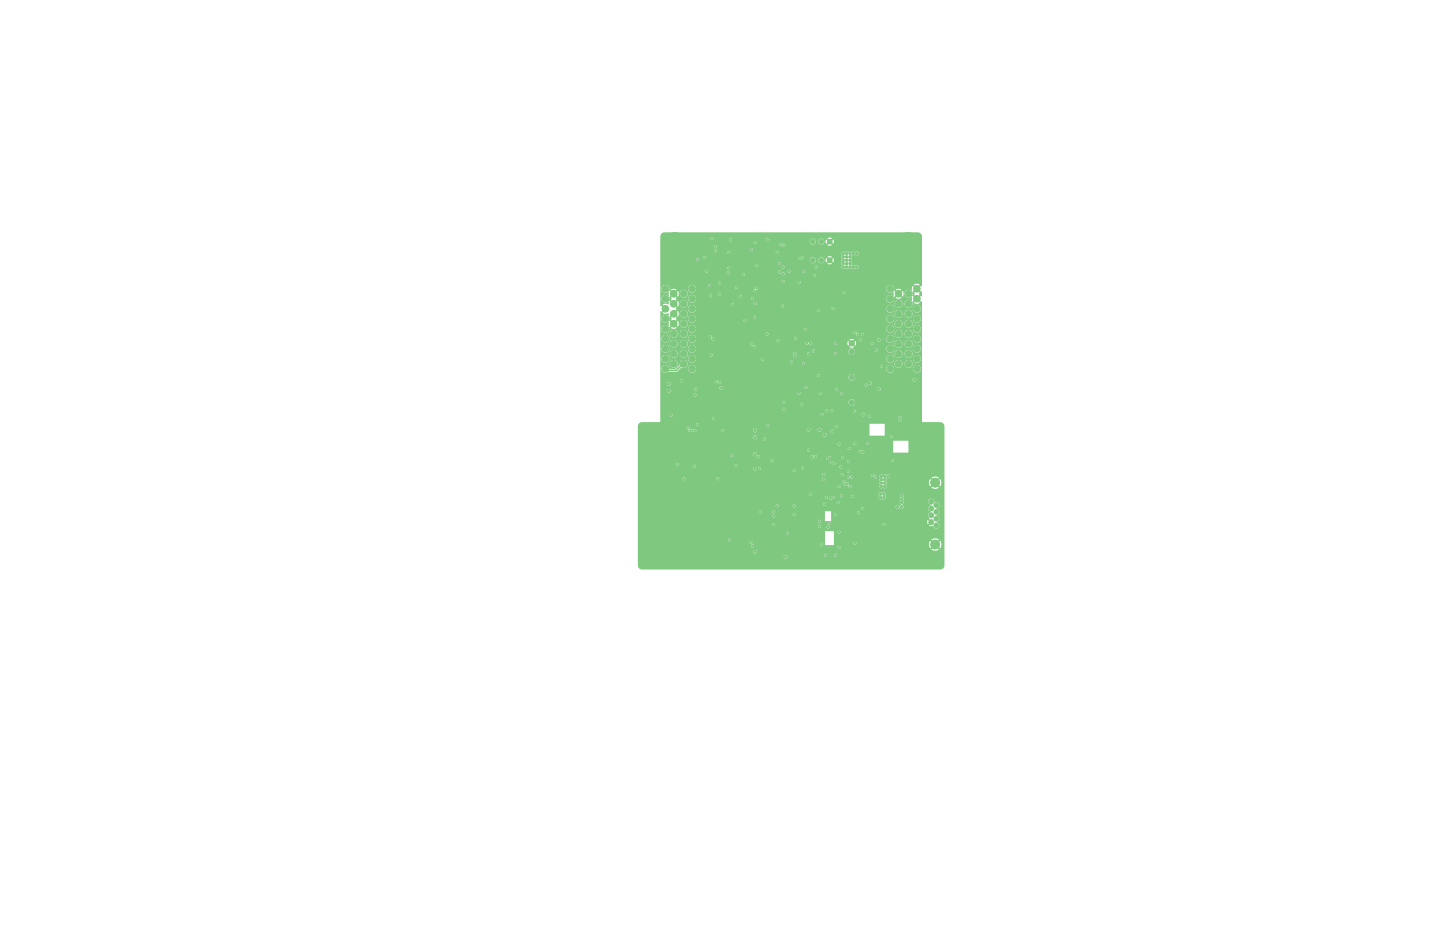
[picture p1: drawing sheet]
<svg xmlns="http://www.w3.org/2000/svg" width="432mm" height="279mm" viewBox="0 0 432 279" stroke-linecap="round" stroke-linejoin="round" font-family="sans-serif">
<g fill="#7fc87f" stroke="#7fc87f" stroke-width=".3">
<circle cx="255.4" cy="102.9" r=".8"/>
<circle cx="255.4" cy="105.5" r=".8"/>
<circle cx="255.4" cy="113.1" r=".8"/>
<circle cx="255.4" cy="120.7" r=".8"/>
<circle cx="202.3" cy="72.9" r="3.2"/>
<circle cx="278.5" cy="130.1" r="3.2"/>
<circle cx="196" cy="165.7" r="3.2"/>
<circle cx="207.5" cy="86.6" r="1"/>
<circle cx="207.5" cy="89.6" r="1"/>
<circle cx="207.5" cy="92.6" r="1"/>
<circle cx="207.5" cy="95.6" r="1"/>
<circle cx="207.5" cy="98.6" r="1"/>
<circle cx="207.5" cy="101.6" r="1"/>
<circle cx="207.5" cy="104.6" r="1"/>
<circle cx="207.5" cy="107.6" r="1"/>
<circle cx="207.5" cy="110.6" r="1"/>
<circle cx="205" cy="88.1" r="1"/>
<circle cx="205" cy="91.1" r="1"/>
<circle cx="205" cy="94.1" r="1"/>
<circle cx="205" cy="97.1" r="1"/>
<circle cx="205" cy="100.1" r="1"/>
<circle cx="205" cy="103.1" r="1"/>
<circle cx="205" cy="106.1" r="1"/>
<circle cx="205" cy="109.1" r="1"/>
<circle cx="202" cy="88.1" r="1"/>
<circle cx="202" cy="91.1" r="1"/>
<circle cx="202" cy="94.1" r="1"/>
<circle cx="202" cy="97.1" r="1"/>
<circle cx="202" cy="100.1" r="1"/>
<circle cx="202" cy="103.1" r="1"/>
<circle cx="202" cy="106.1" r="1"/>
<circle cx="202" cy="109.1" r="1"/>
<circle cx="199.5" cy="86.6" r="1"/>
<circle cx="199.5" cy="89.6" r="1"/>
<circle cx="199.5" cy="92.6" r="1"/>
<circle cx="199.5" cy="95.6" r="1"/>
<circle cx="199.5" cy="98.6" r="1"/>
<circle cx="199.5" cy="101.6" r="1"/>
<circle cx="199.5" cy="104.6" r="1"/>
<circle cx="199.5" cy="107.6" r="1"/>
<circle cx="199.5" cy="110.6" r="1"/>
<circle cx="243.7" cy="78" r=".72"/>
<circle cx="246.3" cy="78" r=".72"/>
<circle cx="248.8" cy="78" r=".72"/>
<circle cx="266.9" cy="110.6" r="1"/>
<circle cx="266.9" cy="107.6" r="1"/>
<circle cx="266.9" cy="104.6" r="1"/>
<circle cx="266.9" cy="101.6" r="1"/>
<circle cx="266.9" cy="98.6" r="1"/>
<circle cx="266.9" cy="95.6" r="1"/>
<circle cx="266.9" cy="92.6" r="1"/>
<circle cx="266.9" cy="89.6" r="1"/>
<circle cx="266.9" cy="86.6" r="1"/>
<circle cx="269.4" cy="109.1" r="1"/>
<circle cx="269.4" cy="106.1" r="1"/>
<circle cx="269.4" cy="103.1" r="1"/>
<circle cx="269.4" cy="100.1" r="1"/>
<circle cx="269.4" cy="97.1" r="1"/>
<circle cx="269.4" cy="94.1" r="1"/>
<circle cx="269.4" cy="91.1" r="1"/>
<circle cx="269.4" cy="88.1" r="1"/>
<circle cx="272.4" cy="109.1" r="1"/>
<circle cx="272.4" cy="106.1" r="1"/>
<circle cx="272.4" cy="103.1" r="1"/>
<circle cx="272.4" cy="100.1" r="1"/>
<circle cx="272.4" cy="97.1" r="1"/>
<circle cx="272.4" cy="94.1" r="1"/>
<circle cx="272.4" cy="91.1" r="1"/>
<circle cx="272.4" cy="88.1" r="1"/>
<circle cx="274.9" cy="110.6" r="1"/>
<circle cx="274.9" cy="107.6" r="1"/>
<circle cx="274.9" cy="104.6" r="1"/>
<circle cx="274.9" cy="101.6" r="1"/>
<circle cx="274.9" cy="98.6" r="1"/>
<circle cx="274.9" cy="95.6" r="1"/>
<circle cx="274.9" cy="92.6" r="1"/>
<circle cx="274.9" cy="89.6" r="1"/>
<circle cx="274.9" cy="86.6" r="1"/>
<circle cx="272.2" cy="72.9" r="3.2"/>
<circle cx="243.7" cy="72.4" r=".72"/>
<circle cx="246.3" cy="72.4" r=".72"/>
<circle cx="248.8" cy="72.4" r=".72"/>
<circle cx="280.8" cy="151.4" r=".72"/>
<circle cx="279.2" cy="150.4" r=".72"/>
<circle cx="279.2" cy="152.4" r=".72"/>
<circle cx="279.2" cy="154.5" r=".72"/>
<circle cx="280.8" cy="153.5" r=".72"/>
<circle cx="280.8" cy="155.5" r=".72"/>
<circle cx="280.8" cy="157.5" r=".72"/>
<circle cx="279.2" cy="156.5" r=".72"/>
<circle cx="280.4" cy="163.2" r="1.35"/>
<circle cx="280.4" cy="144.7" r="1.35"/>
<circle cx="232" cy="158.5" r=".25"/>
<circle cx="264.8" cy="135.4" r=".25"/>
<circle cx="229.2" cy="135.4" r=".25"/>
<circle cx="219.1" cy="134.2" r=".25"/>
<circle cx="257.9" cy="88.9" r=".25"/>
<circle cx="218.6" cy="73.3" r=".25"/>
<circle cx="233.8" cy="88.9" r=".25"/>
<circle cx="220.1" cy="78.3" r=".25"/>
<circle cx="263" cy="74.5" r=".38"/>
<circle cx="214.2" cy="141.5" r=".25"/>
<circle cx="253.6" cy="161.6" r=".25"/>
<circle cx="251.6" cy="100.6" r=".25"/>
<circle cx="214.5" cy="77.8" r=".25"/>
<circle cx="264" cy="72.4" r=".38"/>
<circle cx="263" cy="71.4" r=".38"/>
<circle cx="217.8" cy="129.1" r=".25"/>
<circle cx="243.2" cy="98.9" r=".25"/>
<circle cx="263" cy="73.5" r=".38"/>
<circle cx="261" cy="84.1" r=".25"/>
<circle cx="207.4" cy="140.3" r=".25"/>
<circle cx="240.7" cy="145.6" r=".25"/>
<circle cx="217.8" cy="125.5" r=".25"/>
<circle cx="251.6" cy="128.3" r=".25"/>
<circle cx="229.2" cy="94.8" r=".25"/>
<circle cx="264.8" cy="151.9" r=".38"/>
<circle cx="264" cy="71.4" r=".38"/>
<circle cx="224.4" cy="125.5" r=".25"/>
<circle cx="252.3" cy="97.8" r=".25"/>
<circle cx="270.6" cy="81.6" r=".38"/>
<circle cx="271.4" cy="79.8" r=".38"/>
<circle cx="224.4" cy="120.4" r=".25"/>
<circle cx="265" cy="71.4" r=".38"/>
<circle cx="269.4" cy="128.1" r=".25"/>
<circle cx="265.8" cy="151.9" r=".38"/>
<circle cx="247" cy="144.6" r=".25"/>
<circle cx="254.1" cy="133.7" r=".25"/>
<circle cx="245.7" cy="152.2" r=".25"/>
<circle cx="269.9" cy="156.3" r=".25"/>
<circle cx="269.6" cy="81.6" r=".38"/>
<circle cx="265" cy="72.4" r=".38"/>
<circle cx="259.1" cy="119.4" r=".3"/>
<circle cx="242.9" cy="87.7" r=".3"/>
<circle cx="265" cy="133.1" r=".25"/>
<circle cx="257.9" cy="113.3" r=".25"/>
<circle cx="208.2" cy="133.1" r=".25"/>
<circle cx="214" cy="91.5" r=".25"/>
<circle cx="231" cy="83.6" r=".25"/>
<circle cx="227.5" cy="146.1" r=".25"/>
<circle cx="270.9" cy="144.6" r=".38"/>
<circle cx="213" cy="111.8" r=".25"/>
<circle cx="246" cy="109" r=".25"/>
<circle cx="219.1" cy="137.7" r=".25"/>
<circle cx="271.4" cy="80.8" r=".38"/>
<circle cx="206.4" cy="143.6" r=".25"/>
<circle cx="216.8" cy="108.5" r=".25"/>
<circle cx="270.6" cy="78.5" r=".38"/>
<circle cx="235.1" cy="114.9" r=".25"/>
<circle cx="246.3" cy="161.3" r=".25"/>
<circle cx="273.2" cy="136.7" r=".25"/>
<circle cx="245.7" cy="120.7" r=".25"/>
<circle cx="207.1" cy="124.5" r=".25"/>
<circle cx="257.9" cy="96.1" r=".25"/>
<circle cx="260" cy="97.3" r=".25"/>
<circle cx="254.6" cy="165.4" r=".25"/>
<circle cx="247" cy="164.4" r=".25"/>
<circle cx="242.7" cy="166.4" r=".25"/>
<circle cx="231" cy="118.4" r=".25"/>
<circle cx="207.6" cy="161.6" r=".25"/>
<circle cx="249.3" cy="151.2" r=".25"/>
<circle cx="269.6" cy="78.5" r=".38"/>
<circle cx="206.1" cy="80.3" r=".25"/>
<circle cx="235.3" cy="96.8" r=".25"/>
<circle cx="236.1" cy="154.7" r=".25"/>
<circle cx="233" cy="124.8" r=".25"/>
<circle cx="250.1" cy="108.3" r=".25"/>
<circle cx="224.4" cy="123" r=".25"/>
<circle cx="253.1" cy="89.7" r=".25"/>
<circle cx="233" cy="104.2" r=".25"/>
<circle cx="210.2" cy="143.6" r=".25"/>
<circle cx="270.9" cy="143.3" r=".38"/>
<circle cx="267.3" cy="124.3" r=".25"/>
<circle cx="252.9" cy="165.4" r=".25"/>
<circle cx="221.1" cy="105.2" r=".25"/>
<circle cx="269.9" cy="144.6" r=".38"/>
<circle cx="233.3" cy="107.2" r=".25"/>
<circle cx="213" cy="116.9" r=".25"/>
<circle cx="269.9" cy="143.3" r=".38"/>
<circle cx="246.5" cy="115.4" r=".25"/>
<circle cx="254.9" cy="148.9" r=".25"/>
<circle cx="239.9" cy="123.2" r=".25"/>
<circle cx="219.8" cy="95.3" r=".25"/>
<circle cx="240.2" cy="131.4" r=".25"/>
<circle cx="211.5" cy="161.6" r=".25"/>
<circle cx="250.8" cy="113.6" r=".25"/>
<circle cx="250.1" cy="125.8" r=".25"/>
<circle cx="242.7" cy="127.8" r=".25"/>
<circle cx="265.8" cy="150.9" r=".38"/>
<circle cx="262.8" cy="158.3" r=".25"/>
<circle cx="246" cy="101.9" r=".25"/>
<circle cx="245.7" cy="133.1" r=".25"/>
<circle cx="217.8" cy="127.6" r=".25"/>
<circle cx="257.9" cy="104.9" r=".25"/>
<circle cx="203.1" cy="135.7" r=".25"/>
<circle cx="229" cy="107" r=".25"/>
<circle cx="220.9" cy="85.1" r=".25"/>
<circle cx="242.2" cy="96.3" r=".25"/>
<circle cx="230" cy="76.5" r=".25"/>
<circle cx="263" cy="72.4" r=".38"/>
<circle cx="269.9" cy="160.1" r=".25"/>
<circle cx="229.7" cy="124.8" r=".25"/>
<circle cx="208.2" cy="119.4" r=".25"/>
<circle cx="247" cy="138.2" r=".25"/>
<circle cx="266.8" cy="151.9" r=".38"/>
<circle cx="230.5" cy="86.4" r=".25"/>
<circle cx="248.1" cy="138.3" r=".25"/>
<circle cx="240.2" cy="75.2" r=".25"/>
<circle cx="248.5" cy="93.6" r=".25"/>
<circle cx="247.3" cy="122.5" r=".25"/>
<circle cx="264.8" cy="150.9" r=".38"/>
<circle cx="219.8" cy="98.3" r=".25"/>
<circle cx="212.7" cy="143.6" r=".25"/>
<circle cx="241.7" cy="157.5" r=".25"/>
<circle cx="262.3" cy="124.5" r=".25"/>
<circle cx="253.1" cy="128.3" r=".25"/>
<circle cx="268.9" cy="143.3" r=".38"/>
<circle cx="259" cy="128.8" r=".3"/>
<circle cx="264" cy="153.2" r=".25"/>
<circle cx="201.8" cy="142.3" r=".25"/>
<circle cx="259.5" cy="137.7" r=".25"/>
<circle cx="209.4" cy="140" r=".25"/>
<circle cx="235.8" cy="145.6" r=".25"/>
<circle cx="238.4" cy="127.3" r=".25"/>
<circle cx="258.2" cy="146.4" r=".25"/>
<circle cx="241.2" cy="165.1" r=".38"/>
<circle cx="217.8" cy="71.9" r=".25"/>
<circle cx="259" cy="133.9" r=".25"/>
<circle cx="256.3" cy="132.9" r=".25"/>
<circle cx="247.5" cy="166.4" r=".25"/>
<circle cx="257.9" cy="135.4" r=".25"/>
<circle cx="243.6" cy="137" r=".25"/>
<circle cx="265.3" cy="143.8" r=".38"/>
<circle cx="267.6" cy="138" r=".25"/>
<circle cx="242.9" cy="148.1" r=".25"/>
<circle cx="264.3" cy="144.8" r=".38"/>
<circle cx="260.2" cy="132.9" r=".25"/>
<circle cx="236.1" cy="159.8" r=".25"/>
<circle cx="265.3" cy="144.8" r=".38"/>
<circle cx="246.3" cy="163.1" r=".25"/>
<circle cx="255.6" cy="148.9" r=".25"/>
<circle cx="247.3" cy="151.2" r=".25"/>
<circle cx="264.3" cy="145.8" r=".38"/>
<circle cx="265.3" cy="142.8" r=".38"/>
<circle cx="250.6" cy="166.4" r=".25"/>
<circle cx="264.3" cy="142.8" r=".38"/>
<circle cx="205.1" cy="143.6" r=".25"/>
<circle cx="245.7" cy="156.3" r=".25"/>
<circle cx="266.3" cy="142.8" r=".38"/>
<circle cx="264.3" cy="143.8" r=".38"/>
<circle cx="265.3" cy="145.8" r=".38"/>
<circle cx="253.9" cy="79" r=".38"/>
<circle cx="252.9" cy="78" r=".38"/>
<circle cx="208.2" cy="139.7" r=".25"/>
<circle cx="267.3" cy="130.9" r=".25"/>
<circle cx="229.2" cy="131.6" r=".25"/>
<circle cx="218.6" cy="75.7" r=".25"/>
<circle cx="252.9" cy="79" r=".38"/>
<circle cx="252.9" cy="77" r=".38"/>
<circle cx="270.4" cy="151.9" r=".38"/>
<circle cx="226.2" cy="87.2" r=".25"/>
<circle cx="256.9" cy="76" r=".38"/>
<circle cx="241.4" cy="98.9" r=".25"/>
<circle cx="253.9" cy="80.1" r=".38"/>
<circle cx="253.1" cy="87.7" r=".25"/>
<circle cx="230.2" cy="127.6" r=".25"/>
<circle cx="264" cy="148.1" r=".38"/>
<circle cx="265" cy="148.1" r=".38"/>
<circle cx="253.9" cy="77" r=".38"/>
<circle cx="253.9" cy="78" r=".38"/>
<circle cx="253.9" cy="76" r=".38"/>
<circle cx="239.9" cy="77.5" r=".25"/>
<circle cx="226.2" cy="95" r=".25"/>
<circle cx="208.4" cy="118.4" r=".25"/>
<circle cx="252.9" cy="76" r=".38"/>
<circle cx="255.9" cy="76" r=".38"/>
<circle cx="255.9" cy="80.1" r=".38"/>
<circle cx="265" cy="149.1" r=".38"/>
<circle cx="256.9" cy="80.1" r=".38"/>
<circle cx="213.5" cy="71.4" r=".25"/>
<circle cx="269.1" cy="151.9" r=".38"/>
<circle cx="264" cy="149.1" r=".38"/>
<circle cx="254.9" cy="79" r=".38"/>
<circle cx="270.4" cy="150.7" r=".38"/>
<circle cx="208.7" cy="116.6" r=".25"/>
<circle cx="254.9" cy="80.1" r=".38"/>
<circle cx="222.1" cy="88.9" r=".25"/>
<circle cx="254.9" cy="76" r=".38"/>
<circle cx="270.4" cy="148.6" r=".38"/>
<circle cx="254.9" cy="78" r=".38"/>
<circle cx="257.9" cy="101.9" r=".25"/>
<circle cx="270.4" cy="149.7" r=".38"/>
<circle cx="252.9" cy="80.1" r=".38"/>
<circle cx="260.8" cy="124.8" r=".25"/>
<circle cx="215.3" cy="143.6" r=".25"/>
<circle cx="239.6" cy="84.6" r=".25"/>
<circle cx="218.3" cy="81.8" r=".25"/>
<circle cx="254.9" cy="77" r=".38"/>
<circle cx="219.7" cy="91.3" r=".25"/>
<circle cx="234.6" cy="91.7" r=".25"/>
<circle cx="226.4" cy="140.5" r=".38"/>
<circle cx="226.4" cy="129.1" r=".38"/>
<circle cx="216.3" cy="116.4" r=".38"/>
<circle cx="226.4" cy="131.1" r=".38"/>
<circle cx="274.2" cy="113.8" r=".38"/>
<circle cx="226.4" cy="136.2" r=".38"/>
<circle cx="226.4" cy="165.4" r=".38"/>
<circle cx="215.8" cy="114.6" r=".25"/>
<circle cx="254.6" cy="134.4" r=".25"/>
<circle cx="206.9" cy="129.1" r=".25"/>
<circle cx="208.4" cy="129.1" r=".25"/>
<circle cx="207.6" cy="129.1" r=".25"/>
<circle cx="201.3" cy="124.5" r=".25"/>
<circle cx="239.6" cy="117.9" r=".25"/>
<circle cx="251.6" cy="133.1" r=".25"/>
<circle cx="246.5" cy="124.3" r=".25"/>
<circle cx="263.5" cy="101.9" r=".3"/>
<circle cx="258.7" cy="135.4" r=".3"/>
<circle cx="240.6" cy="140.3" r=".25"/>
<circle cx="256.2" cy="123.2" r=".25"/>
<circle cx="264.3" cy="109.8" r=".25"/>
<circle cx="261.5" cy="102.9" r=".25"/>
<circle cx="265" cy="157.3" r=".25"/>
<circle cx="254.1" cy="145.1" r=".25"/>
<circle cx="250.6" cy="106" r=".25"/>
<circle cx="250.6" cy="102.9" r=".25"/>
<circle cx="245.9" cy="117.9" r=".25"/>
<circle cx="223.4" cy="96.1" r=".25"/>
<circle cx="218.6" cy="80.3" r=".25"/>
<circle cx="226.2" cy="103.9" r=".25"/>
<circle cx="242.5" cy="106" r=".25"/>
<circle cx="238.4" cy="106" r=".25"/>
<circle cx="250.8" cy="127.8" r=".25"/>
<circle cx="250.8" cy="116.6" r=".25"/>
<circle cx="238.1" cy="141" r=".25"/>
<circle cx="252.1" cy="140" r=".25"/>
<circle cx="233" cy="151.6" r=".25"/>
<circle cx="232" cy="154.7" r=".25"/>
<circle cx="249.6" cy="129.3" r=".38"/>
<circle cx="242.4" cy="128.8" r=".38"/>
<circle cx="247.3" cy="130.4" r=".38"/>
<circle cx="245.7" cy="128.8" r=".38"/>
<circle cx="259" cy="124.3" r=".38"/>
<circle cx="200.5" cy="117.1" r=".38"/>
<circle cx="252.3" cy="117.9" r=".25"/>
<circle cx="263.5" cy="116.6" r=".38"/>
<circle cx="249.5" cy="123.1" r=".25"/>
<circle cx="247.8" cy="123.2" r=".25"/>
<circle cx="204.3" cy="114.1" r=".3"/>
<circle cx="244.7" cy="80.1" r=".25"/>
<circle cx="234.1" cy="73.4" r=".25"/>
<circle cx="212.8" cy="85.6" r=".25"/>
<circle cx="212" cy="81.3" r=".25"/>
<circle cx="211.2" cy="77.3" r=".25"/>
<circle cx="213" cy="88.7" r=".25"/>
<circle cx="231.5" cy="138" r=".25"/>
<circle cx="242.5" cy="134.9" r=".25"/>
<circle cx="220.7" cy="139.6" r=".25"/>
<circle cx="250.1" cy="139" r=".25"/>
<circle cx="258.7" cy="100.3" r=".25"/>
<circle cx="240.7" cy="77.3" r=".25"/>
<circle cx="244.2" cy="82.6" r=".25"/>
<circle cx="249.8" cy="92.5" r=".25"/>
<circle cx="234.8" cy="80.1" r=".25"/>
<circle cx="233.8" cy="79" r=".25"/>
<circle cx="257.2" cy="100.3" r=".25"/>
<circle cx="236.6" cy="81.3" r=".25"/>
<circle cx="240.9" cy="81.3" r=".25"/>
<circle cx="245.5" cy="93" r=".25"/>
<circle cx="235.1" cy="73.5" r=".25"/>
<circle cx="220.9" cy="86.2" r=".25"/>
<circle cx="214.5" cy="75.2" r=".25"/>
<circle cx="225.7" cy="89.5" r=".25"/>
<circle cx="209.2" cy="77.8" r=".25"/>
<circle cx="226.4" cy="72.6" r=".25"/>
<circle cx="230" cy="71.9" r=".25"/>
<circle cx="219.1" cy="71.9" r=".25"/>
<circle cx="222.9" cy="82.3" r=".25"/>
<circle cx="214.5" cy="74" r=".25"/>
<circle cx="203.1" cy="139.2" r=".25"/>
<circle cx="249.4" cy="138.7" r=".25"/>
<circle cx="228.7" cy="107.7" r=".25"/>
<circle cx="225.4" cy="103.2" r=".25"/>
<circle cx="225.2" cy="162.6" r=".25"/>
<circle cx="218.8" cy="161.8" r=".25"/>
<circle cx="258.7" cy="152.4" r=".25"/>
<circle cx="225.7" cy="163.6" r=".25"/>
<circle cx="257.4" cy="153.7" r=".25"/>
<circle cx="232" cy="157.3" r=".25"/>
<circle cx="252.5" cy="142.3" r=".25"/>
<circle cx="247.8" cy="149.1" r=".25"/>
<circle cx="251.6" cy="159.6" r=".25"/>
<circle cx="254.4" cy="143" r=".25"/>
<circle cx="253.1" cy="144.3" r=".25"/>
<circle cx="244" cy="105.2" r=".25"/>
<circle cx="232" cy="153.5" r=".25"/>
<circle cx="228" cy="153.5" r=".25"/>
<circle cx="255.4" cy="143" r=".25"/>
<circle cx="253.4" cy="145.1" r=".25"/>
<circle cx="248.3" cy="158" r=".25"/>
<circle cx="245.7" cy="157.8" r=".25"/>
<circle cx="250.6" cy="154.3" r=".25"/>
<circle cx="248.8" cy="157" r=".25"/>
<circle cx="251.3" cy="150.7" r=".25"/>
<circle cx="249.8" cy="149.1" r=".25"/>
<circle cx="249.1" cy="149.4" r=".25"/>
<circle cx="254.4" cy="141.3" r=".25"/>
<circle cx="245.4" cy="112.6" r=".25"/>
<circle cx="238.6" cy="101.4" r=".25"/>
<circle cx="233.3" cy="102.2" r=".25"/>
<circle cx="241.9" cy="102.9" r=".25"/>
<circle cx="248.8" cy="137.2" r=".25"/>
<circle cx="259.7" cy="115.4" r=".25"/>
<circle cx="226.4" cy="91" r=".25"/>
<circle cx="234.8" cy="84.4" r=".25"/>
<circle cx="226.9" cy="86.4" r=".25"/>
<circle cx="226.9" cy="79.5" r=".25"/>
<circle cx="261" cy="114.9" r=".25"/>
<circle cx="248.1" cy="137.5" r=".25"/>
<circle cx="233.8" cy="81.5" r=".25"/>
<circle cx="233" cy="75.7" r=".25"/>
<circle cx="214.8" cy="114.3" r=".25"/>
<circle cx="216.8" cy="129.1" r=".25"/>
<circle cx="254.4" cy="138.3" r=".25"/>
<circle cx="227.7" cy="140.5" r=".25"/>
<circle cx="251.6" cy="164.1" r=".25"/>
<circle cx="256.4" cy="162.9" r=".25"/>
<circle cx="225.4" cy="74.7" r=".25"/>
<circle cx="234.8" cy="82.1" r=".25"/>
<circle cx="214" cy="125.5" r=".25"/>
<circle cx="209.2" cy="127.3" r=".25"/>
<circle cx="230" cy="100.1" r=".25"/>
<circle cx="256.4" cy="99.6" r=".25"/>
<circle cx="262.8" cy="104.9" r=".25"/>
<circle cx="240.3" cy="121.3" r=".25"/>
<circle cx="244.5" cy="136.9" r=".25"/>
<circle cx="235.1" cy="122.7" r=".25"/>
<circle cx="235.1" cy="120.7" r=".25"/>
<circle cx="261.7" cy="142.5" r=".25"/>
<circle cx="269.9" cy="125.3" r=".25"/>
<circle cx="262.5" cy="143" r=".25"/>
<circle cx="269.9" cy="126.1" r=".25"/>
<circle cx="240.9" cy="109" r=".25"/>
<circle cx="213" cy="100.9" r=".25"/>
<circle cx="213.2" cy="106.5" r=".25"/>
<circle cx="241.7" cy="116.1" r=".25"/>
<circle cx="242.9" cy="102.9" r=".25"/>
<circle cx="213.7" cy="101.6" r=".25"/>
<circle cx="215.8" cy="88.2" r=".25"/>
<circle cx="215.8" cy="84.8" r=".25"/>
<circle cx="238.1" cy="154.2" r=".25"/>
<circle cx="238.1" cy="151.7" r=".25"/>
<circle cx="200.5" cy="115.1" r=".38"/>
<circle cx="235.6" cy="166.9" r=".38"/>
<circle cx="227.5" cy="137" r=".25"/>
<circle cx="219.3" cy="136.4" r=".25"/>
<circle cx="206.3" cy="128.3" r=".25"/>
<circle cx="251.6" cy="145.8" r=".25"/>
<circle cx="252.3" cy="148.6" r=".25"/>
<circle cx="254.9" cy="145.8" r=".25"/>
<circle cx="247" cy="142.3" r=".25"/>
<circle cx="247" cy="143.8" r=".3"/>
<circle cx="252.6" cy="137.1" r=".25"/>
<circle cx="238.4" cy="106.7" r=".25"/>
<circle cx="237.4" cy="108.5" r=".25"/>
</g>
<path d="M204.8 109.1l-2 1.9h-2.8" fill="none" stroke="#7fc87f" stroke-width=".51"/>
<g fill="#7fc87f">
<path d="M198.4 70l.9-.4 76.1 .1 .8 .5 .3 .7v14.8h-.3l-.6 .6-.4-.4 .5-.6a1.5 1.5 0 0 0-1.6 0l.6 .6-.4 .4-.6-.6-.3 .8 .1 .9a1.25 1.25 0 0 0-1.9-.2 1.25 1.25 0 0 0 .1 1.9 1.25 1.25 0 0 0 1.8-.3l-.1 1.6a1.2 1.2 0 0 0-2 .1 1.2 1.2 0 0 0 1.1 1.8 1.2 1.2 0 0 0 1-1.8l.8-.6 .4 .3-.6 .6a1.49 1.49 0 0 0 1.7 0l-.6-.6 .4-.3 .6 .5h.3v35.9l.2 .2 5.4 .1 .7 .3 .4 .7v41.9a1.27 1.27 0 0 1-1.3 1.2h-89.8a1.27 1.27 0 0 1-.8-1.2v-2.5h43.7a.56 .56 0 0 0 .9 .4 .56 .56 0 0 0 0-.9 .56 .56 0 0 0-.9 .4l-43.7 .1v-.6h55.8l.4 .5 .4-.2 .1-.3h2.1a.44 .44 0 0 0 .6 .4 .44 .44 0 0 0 .2-.7 .44 .44 0 0 0-.7 .2l-2.2 .1-.5-.4-.4 .4h-55.8v-.9h34.6a.56 .56 0 0 0 .8 .4 .56 .56 0 0 0 0-1 .56 .56 0 0 0-.8 .4l-34.6 .2v-1.4h59.9a.44 .44 0 0 0 .5 .4 .44 .44 0 0 0 .2-.7 .44 .44 0 0 0-.7 .2l-59.9 .1v-.5h34a.44 .44 0 0 0 .5 .5 .44 .44 0 0 0 .2-.8 .44 .44 0 0 0-.7 .2l-34 .1v-.5h54.5a.44 .44 0 0 0 .6 .5 .44 .44 0 0 0 .2-.7 .44 .44 0 0 0-.8 .1l-54.5 .1v-.6h33.4a.44 .44 0 0 0 .6 .5 .44 .44 0 0 0 .2-.7 .44 .44 0 0 0-.7 .1l-33.5 .1v-.7h27.1a.44 .44 0 0 0 .6 .5 .44 .44 0 0 0 .1-.7 .44 .44 0 0 0-.7 .1l-27.1 .1v-2h44.4a.44 .44 0 0 0 .5 .4 .44 .44 0 0 0 .2-.7 .44 .44 0 0 0-.7 .1l-44.4 .2v-.6h56.1v4.2h2.6v-.6h5.9l.4 .5 .4-.2h21.9l.3 1.3 .6-.6 .4 .3-.5 .7a1.85 1.85 0 0 0 2.1-.1l-.6-.6 .4-.3 .7 .5a1.85 1.85 0 0 0-.1-2.2l-.6 .6-.4-.4 .5-.6a1.85 1.85 0 0 0-2.1 .1l.6 .5-.4 .4-.6-.6-.3 1h-21.9a.43 .43 0 0 0-.2-.7 .43 .43 0 0 0-.6 .4h-5.9v-3.3l1.2 .1a.44 .44 0 0 0 .6 .3 .44 .44 0 0 0 0-.7 .44 .44 0 0 0-.6 .3h-1.2v-.3h-2.6h-56.1v-1.5h54l.4 .5 .4-.2h1.8a.44 .44 0 0 0 .5 .5 .44 .44 0 0 0 .2-.8 .44 .44 0 0 0-.7 .2l-1.8 .1v-.4l-.3-.3-.5 .4h-54v-.5h40.3a.43 .43 0 0 0 .6 .5 .43 .43 0 0 0 .1-.7h16.1l.3 .5 .5-.3 15.4 .1a.44 .44 0 0 0 .7 .3 .44 .44 0 0 0 0-.7 .44 .44 0 0 0-.7 .3h-15.4v-.3l-.4-.3-.4 .4-16.4-.2-.4 .4h-40.3v-1h54l.4 .5 .4-.3h31.9l.2 .8 .6-.6 .4 .3-.6 .7 1.1 .1a1 1 0 0 0 1.1 .8 1 1 0 0 0 .9-1 1 1 0 0 0-.9-1 1.03 1.03 0 0 0 .9-1 1.03 1.03 0 0 0-.9-1.1 1.03 1.03 0 0 0 .9-1 1.03 1.03 0 0 0-.9-1 .99 .99 0 0 0 .8-1.3 .99 .99 0 0 0-1.4-.5 .94 .94 0 0 0-.9-1.1 .94 .94 0 0 0-1 .9 .94 .94 0 0 0 .9 1 1.07 1.07 0 0 0-.9 1.1 1.07 1.07 0 0 0 .9 1 1.08 1.08 0 0 0-.8 .8 1.08 1.08 0 0 0 .3 1.1l-.1 .1 .6 .6-.4 .4-.6-.7-.2 .6h-31.9v-.4l-.3-.2-.5 .4h-54v-1.5l40.3 .1a.44 .44 0 0 0 .7 .3 .44 .44 0 0 0 0-.7 .44 .44 0 0 0-.7 .3h-40.3v-.5l46.4 .1a.44 .44 0 0 0 .7 .3 .44 .44 0 0 0 0-.7 .44 .44 0 0 0-.7 .3h-46.4v-.8h36.2l.4 .5 .3-.1 .2-.4h3.2a.44 .44 0 0 0 .5 .5 .44 .44 0 0 0 .3-.6h15v2.9h1.8v-2l.9 .2a.44 .44 0 0 0 .7 .3 .44 .44 0 0 0 0-.8 .44 .44 0 0 0-.7 .3h-.9v-.5h7.8a.44 .44 0 0 0 .6 .4 .44 .44 0 0 0 .1-.7 .44 .44 0 0 0-.7 .2l-7.8 .1v-.4h-16.8l-.3-.3-.5 .4h-3.2l-.4-.4-.5 .4h-36.2v-1h67a.44 .44 0 0 0 .5 .5 .44 .44 0 0 0 .2-.7 .44 .44 0 0 0-.7 .1l-67 .1v-.8h41.3l.4 .5 .3-.1 .2-.4h4.2l.4 .5 30.5-.1 .4 .5 .7-.4 .2 .2a.62 .62 0 0 0 1-.2 .62 .62 0 0 0-.4-.9l.4-.5-.2-.5 .2-.6-.2-.4a.61 .61 0 0 0 .1-.9 .61 .61 0 0 0-.9 0 .61 .61 0 0 0 .1 .9l-.2 .5 .2 .4a.87 .87 0 0 0 .2 1.3l-.4 .4a.63 .63 0 0 0-.7-.4 .63 .63 0 0 0-.5 .5v.1h-30.1a.44 .44 0 0 0-.2-.7 .44 .44 0 0 0-.6 .3h-4.2l-.4-.4-.5 .4h-41.3v-.5h55.5a.44 .44 0 0 0 .6 .5 .44 .44 0 0 0 .2-.7 .44 .44 0 0 0-.7 .1l-55.6 .1v-.5h59.6a.44 .44 0 0 0 .6 .5 .44 .44 0 0 0 .2-.7 .44 .44 0 0 0-.8 .1l-59.6 .1v-1.5h56l.4 .5 1-.3 .3 .5 .5-.1a.48 .48 0 0 0 .7-.4 .48 .48 0 0 0-.6-.6l-.7 .3-.2 .3h-.5v-.3l-.4-.3-.5 .4h-56v-.5h60.6l.4 .5 .4-.3 2.5 .1a.44 .44 0 0 0 .7 .4 .44 .44 0 0 0 0-.8 .44 .44 0 0 0-.7 .3h-2.5v-.3l-.3-.3-.5 .4h-60.6v-.5h51.2l.4 .5 .5-.4h20.1l.2 .4a.65 .65 0 0 0 0 1 .65 .65 0 0 0 .9-.1 .63 .63 0 0 0 .9-.1 .63 .63 0 0 0-.1-.9 .63 .63 0 0 0-.1-.8 .63 .63 0 0 0-.9 .1l-.6-.2-.3 .6h-20.1l-.4-.5-.5 .4h-51.2v-2.3h59.9a.44 .44 0 0 0 .5 .5 .44 .44 0 0 0 .2-.8 .44 .44 0 0 0-.7 .2l-59.9 .1v-2.3h13.4l.3 .5 .4-.1 .1-.4h9.3l.4 .5 .5-.3h30.8l.5 .6h5.7l.3 .5a.59 .59 0 0 0 .2 .6 .59 .59 0 0 0 .7 0l.6 .1a.47 .47 0 0 0 0 .7 .47 .47 0 0 0 .7-.1 .47 .47 0 0 0-.3-.7l-.3 .1a.66 .66 0 0 0-.2-.8 .66 .66 0 0 0-.8 0l-.1-.1a.44 .44 0 0 0-.3-.7 .44 .44 0 0 0-.5 .4h-5.5a.48 .48 0 0 0 .1-.9 .48 .48 0 0 0-.8 .3h-30.8v-.3l-.4-.3-.5 .4h-9.3l-.3-.4-.5 .4h-13.4v-.5h62.6a.54 .54 0 0 0 .5 .5 .54 .54 0 0 0 .6-.3 .45 .45 0 0 0 .7 .2 .45 .45 0 0 0-.1-.8 .45 .45 0 0 0-.7 .3l-.6-.3-.4 .4h-62.6v-.8h55.3l.4 .5 .3-.1 .1-.3h4.7l.4 .5 .4-.3h8.4l.2 .4h.5a.47 .47 0 0 0 .5 .6 .47 .47 0 0 0 .4-.6h.8l.2 .4-.2 .4 .2 .6-.2 .5 .2 .4a.69 .69 0 0 0 0 1 .69 .69 0 0 0 1 0 .63 .63 0 0 0 .9-.1 .63 .63 0 0 0-.1-.9l.1-.6h12.8l.3 1.2 .6-.6 .4 .4-.6 .6 .3 .2a1.85 1.85 0 0 0 1.9-.2l-.6-.6 .4-.4 .7 .5a1.85 1.85 0 0 0-.1-2.1l-.6 .6-.4-.4 .5-.6a1.85 1.85 0 0 0-2.1 0l.6 .6-.4 .4-.6-.6-.3 1h-12.8l-.2-.3 .3-.4-.3-.6 .2-.2a.61 .61 0 0 0 .9 .1 .61 .61 0 0 0 0-.9 .61 .61 0 0 0-.9 .2l-.4-.3-.6 .3-.6-.3-.4 .3-.1 .4-1.4-.3a.53 .53 0 0 0-.4-.4 .53 .53 0 0 0-.6 .3h-8.4v-.4l-.3-.2-.5 .4h-4.7l-.3-.4-.5 .3h-55.3v-1.6h34.6l.5 .5 11.3-.1 .4 .5 .4-.3h15.4a.44 .44 0 0 0 .6 .5 .44 .44 0 0 0 .2-.7 .44 .44 0 0 0-.7 .1l-15.5 .1v-.3l-.3-.3-.5 .4h-10.9l.2-.5h.3a.44 .44 0 0 0 .5 .4 .44 .44 0 0 0 .3-.7l12.1 .2a.44 .44 0 0 0 .7 .3 .44 .44 0 0 0 0-.8l10.7 .2a.44 .44 0 0 0 .7 .3 .44 .44 0 0 0 0-.8 .44 .44 0 0 0-.7 .3h-11l-.4 .3h-12.1l-.4-.1-.4 .4-.9-.5-.4 .2-.1 .4h-34.6v-.9h16.4l.2 .4 .3 .1 .3-.2 .1-.4h11.7a.44 .44 0 0 0 .5 .5 .44 .44 0 0 0 .2-.8 .44 .44 0 0 0-.7 .2l-11.7 .1-.5-.3-.4 .4h-16.4v-.5h11.3a.44 .44 0 0 0 .6 .5 .44 .44 0 0 0 .2-.8 .44 .44 0 0 0-.7 .2l-11.4 .1v-.6h57.7l.2 .4 .3 .1a.5 .5 0 0 0 .6 .3 .5 .5 0 0 0 .4-.6 .5 .5 0 0 0-.7-.3l-.4-.3-.4 .4h-57.7v-.7h39.8l.4 .5 .4-.2 22.1 .1a.43 .43 0 0 0 .7 .4 .43 .43 0 0 0 0-.8l12.5 .1a.44 .44 0 0 0 .6 .3 .44 .44 0 0 0 0-.7 .44 .44 0 0 0-.6 .3h-12.8l-.4 .3h-22.1v-.4l-.3-.3-.5 .4h-39.8v-.5h56.4a.56 .56 0 0 0 .4 .5 .56 .56 0 0 0 .6-.3l.4-.1 .1-.4 3 .1a.44 .44 0 0 0 .7 .3 .44 .44 0 0 0 0-.7 .44 .44 0 0 0-.7 .3h-3l-.5-.3-.8 .3-.2 .3h-56.4v-.5h35.7l.4 .5 .3-.1 .2-.4h15.2l.4 .5 .5-.3a.46 .46 0 0 0 .6 .3 .46 .46 0 0 0 .3-.6 .46 .46 0 0 0-.6-.2l-.3 .2-.6-.2-.3 .3h-15.2l-.4-.4-.5 .4h-35.7v-.5h27.6a.44 .44 0 0 0 .5 .5 .44 .44 0 0 0 .3-.6l6.2 .1a.56 .56 0 0 0 1 .2 .56 .56 0 0 0-.3-.9 .56 .56 0 0 0-.7 .6h-6.2l-.4-.3-.4 .4h-27.6v-1h66.2l.3 .4 .8 .1 .5-.2h13.3v-3.6h-4.6v3.6l-8.7-.1a.54 .54 0 0 0-.2-.6 .54 .54 0 0 0-.7 .1l-.4-.1-.3 .4h-66.2v-.5l50.7 .1a.44 .44 0 0 0 .7 .3 .44 .44 0 0 0 0-.7 .44 .44 0 0 0-.7 .3h-50.7v-.5l62.9 .1a.44 .44 0 0 0 .7 .3 .44 .44 0 0 0 0-.8 .44 .44 0 0 0-.7 .4h-62.9v-1.3l59.8 .1a.43 .43 0 0 0 .7 .3 .43 .43 0 0 0 .1-.7h4l.4 .5 .4-.1 .1-.4 3 .1a.44 .44 0 0 0 .7 .4 .44 .44 0 0 0 0-.8 .44 .44 0 0 0-.7 .3h-3l-.5-.3-.4 .3-4.4-.1-.4 .4h-59.8v-1.9h34.6l.5 .5 2.4-.1a.44 .44 0 0 0 .6 .4 .44 .44 0 0 0 .2-.7 .44 .44 0 0 0-.8 .2l-2 .1a.56 .56 0 0 0-.1-1 .56 .56 0 0 0-.8 .6h-34.6v-.8h55.4l.5 .5h19.7a.44 .44 0 0 0 .7 .3 .44 .44 0 0 0 0-.7 .44 .44 0 0 0-.7 .3h-19.3l.2-.2h17.5v-3.6h-4.6v3.6h-12.9a.56 .56 0 0 0-.4-.8 .56 .56 0 0 0-.7 .6h-55.4v-2.1h14.6l.2 .4 .4 .1a.57 .57 0 0 0 .2 .7 .57 .57 0 0 0 .7-.1h.5a.57 .57 0 0 0 .9-.4h7.6l.3 .5 .5-.3h8.7a.56 .56 0 0 0 .4 .4 .56 .56 0 0 0 .6-.2l22.1 .1a.56 .56 0 0 0 1 .2 .56 .56 0 0 0-.3-.9 .56 .56 0 0 0-.7 .6h-22.1l.1-.5h14.9a.56 .56 0 0 0 .5 .5 .56 .56 0 0 0 .6-.5l2.2 .1a.56 .56 0 0 0 1 .2 .56 .56 0 0 0-.3-.9 .56 .56 0 0 0-.7 .6h-2.2l-.1-.4-.4-.2-.4 .1-.2 .5h-14.9l-.6-.4-.4 .2-.1 .5h-8.7l-.4-.6-.4 .4h-7.6l-.3-.4-1 .1a.54 .54 0 0 1-.6 0 .54 .54 0 0 1-.2-.6l-.5-.2-.3 .4h-14.6v-.5l.1-.6h17.3l.4 .5 .5-.2h20.2l.4 .5 .4-.2h19.8a.44 .44 0 0 0 .6 .4 .44 .44 0 0 0 .1-.7 .44 .44 0 0 0-.7 .1l-19.8 .2 .1-.4-.4-.3-.5 .4h-20.2a.43 .43 0 0 0-.3-.6 .43 .43 0 0 0-.6 .3h-17.3l.9-.6 5.5-.1 .2-.2v-.8h15.6a.43 .43 0 0 0 .5 .4 .43 .43 0 0 0 .2-.7h55.1l.2 .5a.48 .48 0 0 0 0 .7 .48 .48 0 0 0 .7-.1 .48 .48 0 0 0-.1-.7 .44 .44 0 0 0-.1-.7 .44 .44 0 0 0-.7 .3l-55.5-.1-.3 .4h-15.6v-1h2.9a.44 .44 0 0 0 .5 .4 .44 .44 0 0 0 .2-.7h44.5l.3 .5 .5-.4h11.5l.5 .5h1.4a.44 .44 0 0 0 .7 .3 .44 .44 0 0 0 0-.7 .44 .44 0 0 0-.7 .3h-1a.56 .56 0 0 0-.1-1 .56 .56 0 0 0-.8 .6h-11.5l-.1-.3-.4-.1-.3 .3h-44.5l-.4-.1-.3 .4h-2.9v-1.4h49.3l.4 .5 .4-.2 .1-.3h.8l.4 .5 .5-.4h5.8a.44 .44 0 0 0 .6 .5 .44 .44 0 0 0 .2-.8 .44 .44 0 0 0-.7 .2l-5.9 .1-.2-.4-.3-.1-.4 .4h-.8l-.5-.4-.4 .4h-49.3v-.5l36.6 .1a.44 .44 0 0 0 .7 .3 .44 .44 0 0 0 0-.7 .44 .44 0 0 0-.7 .3h-36.6v-1.3h41.8a.44 .44 0 0 0 .6 .4 .44 .44 0 0 0 .2-.7 .44 .44 0 0 0-.7 .2l-41.9 .1v-.7h36.6l.2 .4 .3 .1 .4-.5h18.9a.98 .98 0 0 0 1.3 1 .98 .98 0 0 0 .4-1.6 .98 .98 0 0 0-1.6 .4l-.1 .2h-18.9l-.5-.3-.4 .3h-36.6v-2.2l10 .1a.44 .44 0 0 0 .6 .3 .44 .44 0 0 0 0-.8 .44 .44 0 0 0-.6 .4h-10v-.6h41.2l.3 .5 .4-.1 .1-.4h5.5l.4 .5 .3-.1 .2-.3h5.5a.44 .44 0 0 0 .6 .4 .44 .44 0 0 0 .2-.7 .44 .44 0 0 0-.8 .1l-5.5 .2-.5-.4-.4 .3h-5.5l-.5-.3-.3 .3h-41.2v-.6h2a.56 .56 0 0 0 .8 .4 .56 .56 0 0 0 0-.9 .56 .56 0 0 0-.8 .4l-2 .1v-.6h10.2l.2 .4 .3 .1 .4-.3-.1-.4h6.7a.56 .56 0 0 0 .5 .5 .56 .56 0 0 0 .6-.3h33.6l.4 .5 .5-.4h11.7a.56 .56 0 0 0 .8 .4 .56 .56 0 0 0 0-.9 .56 .56 0 0 0-.8 .4l-11.7 .1-.1-.3-.4-.2-.4 .4h-33.6v-.5h24.4a.44 .44 0 0 0 .6 .4 .44 .44 0 0 0 .2-.7 .44 .44 0 0 0-.7 .2l-24.5 .1-.6-.3-.3 .2-.2 .4h-6.7l-.4-.2-.4 .4h-10.2v-1.4h2a.56 .56 0 0 0 .4 .5 .56 .56 0 0 0 .6-.3l58.3 .1a.44 .44 0 0 0 .6 .3 .44 .44 0 0 0 0-.7 .44 .44 0 0 0-.6 .3l-58.2-.1a.56 .56 0 0 0-.5-.7 .56 .56 0 0 0-.6 .6h-2v-1.2h5.9l.4 .6 .5-.3h9.5a.56 .56 0 0 0 .4 .5 .56 .56 0 0 0 .6-.2l.4 .4 .5-.2h44.4a.44 .44 0 0 0 .5 .5 .44 .44 0 0 0 .2-.7 .44 .44 0 0 0-.7 .1l-44.4 .1-.2-.5-.7 .1-.5-.5-.5 .4h-9.5a.48 .48 0 0 0-.3-.7 .48 .48 0 0 0-.6 .4h-5.9v-1.5h47l.3 .5h9.1a.98 .98 0 0 0 .5 .9 .98 .98 0 0 0 1 0l17.8 .2a.56 .56 0 0 0 .9 .1 .56 .56 0 0 0-.2-.9 .56 .56 0 0 0-.8 .6l-17.6-.1a.98 .98 0 0 0-.1-1.6 .98 .98 0 0 0-1.5 .8l-8.7-.1a.44 .44 0 0 0-.1-.7 .44 .44 0 0 0-.6 .3h-47v-2h.4a1.2 1.2 0 0 0 .6 1.1 1.2 1.2 0 0 0 1.3-.1l2.7-.1 1-.9h2.4v.2a1.18 1.18 0 0 0 1.2 1.1 1.18 1.18 0 0 0 1.1-1.3h57.1v.2a1.18 1.18 0 0 0 1.2 1.1 1.18 1.18 0 0 0 1.1-1.3h5.7v.2a1.18 1.18 0 0 0 1.8 .9 1.18 1.18 0 0 0 0-2 1.18 1.18 0 0 0-1.8 .9h-5.7v-.2a1.18 1.18 0 0 0-1.3-.9 1.18 1.18 0 0 0-1 1.1h-57.1l-.4-.8h55.6a.44 .44 0 0 0 .5 .5 .44 .44 0 0 0 .2-.7 .44 .44 0 0 0-.7 .1l-55.6 .1a1.18 1.18 0 0 0-1.2-.2 1.18 1.18 0 0 0-.7 1h-2.4l.3-.4a1.27 1.27 0 0 0 1.9-1.1h34.3l.4 .4h.3l.1-.4h27v.2a1.18 1.18 0 0 0 1.2 1.1 1.18 1.18 0 0 0 1.1-1.3h.7v.2a1.18 1.18 0 0 0 1.8 .9 1.18 1.18 0 0 0 0-2 1.18 1.18 0 0 0-1.8 .9h-.7v-.2a1.18 1.18 0 0 0-1.3-.9 1.18 1.18 0 0 0-1 1.1h-27l-.3-.4-.5 .4h-34.3v-.2a1.21 1.21 0 0 0-1.5-.9 1.21 1.21 0 0 0-.9 1.5l-1.2 1.2h-1.8a1.25 1.25 0 0 0-1.1-1.2 1.25 1.25 0 0 0-1.3 1.1h-.4v-1.5h2.9a1.18 1.18 0 0 0 1.6 1.2 1.18 1.18 0 0 0 .3-2 1.18 1.18 0 0 0-1.9 .7l-2.9 .1v-1.5h.4v.2a1.18 1.18 0 0 0 1.2 1.1 1.18 1.18 0 0 0 1.1-1.3h5.7v.2a1.18 1.18 0 0 0 .7 1 1.18 1.18 0 0 0 1.2-.3l28.6 .2a.44 .44 0 0 0 .7 .3 .44 .44 0 0 0 0-.8 .44 .44 0 0 0-.7 .3h-28.6l.4-.7h19.6a.44 .44 0 0 0 .5 .5 .44 .44 0 0 0 .3-.7h36.7v.2a1.18 1.18 0 0 0 1.2 1.1 1.18 1.18 0 0 0 1.1-1.3h5.7v.2a1.18 1.18 0 0 0 1.8 .9 1.18 1.18 0 0 0 0-2 1.18 1.18 0 0 0-1.8 .9h-5.7v-.2a1.18 1.18 0 0 0-1.3-.9 1.18 1.18 0 0 0-1 1.1h-36.7l-.4-.2-.4 .4h-19.6l-.3-.9-.6-.4h5a.44 .44 0 0 0 .6 .5 .44 .44 0 0 0 .2-.7 .44 .44 0 0 0-.8 .1l-5.5 .1-.7 .4-.2 .7h-5.7v-.2a1.18 1.18 0 0 0-1.3-.9 1.18 1.18 0 0 0-1 1.1h-.4v-1.5h2.9a1.18 1.18 0 0 0 1.1 1.3 1.18 1.18 0 0 0 1.2-1.3h.7v.2a1.18 1.18 0 0 0 1.3 1.1 1.18 1.18 0 0 0 1-1.4h31.7l.1 .3a.5 .5 0 0 0 0 .7 .5 .5 0 0 0 .7 0 .5 .5 0 0 0 0-.7l.1-.2h3.3a.43 .43 0 0 0 .4 .5 .43 .43 0 0 0 .4-.6l7.2 .1a.44 .44 0 0 0 .7 .3 .44 .44 0 0 0 0-.7 .44 .44 0 0 0-.7 .3h-7.2l-.5-.3-.3 .4h-3.3l-.4-.5-.5 .4h-31.7a1.18 1.18 0 0 0-1.2-1 1.18 1.18 0 0 0-1.1 1.1h-.7v-.2a1.18 1.18 0 0 0-1.3-.9 1.18 1.18 0 0 0-1 1.1h-2.9v-1.5h.4a1.18 1.18 0 0 0 1.1 1.3 1.18 1.18 0 0 0 1.2-1.3h5.7v.2a1.18 1.18 0 0 0 .9 1 1.18 1.18 0 0 0 1.3-.6h34.9l.4 .5 .5-.2h10v.2a.98 .98 0 0 0 .8 .8 .98 .98 0 0 0 1-.4h12.1v.2a1.18 1.18 0 0 0 1.2 1.1 1.18 1.18 0 0 0 1.1-1.3h.7v.2a1.18 1.18 0 0 0 1.8 .9 1.18 1.18 0 0 0 0-2 1.18 1.18 0 0 0-1.8 .9h-.7v-.2a1.18 1.18 0 0 0-1.3-.9 1.18 1.18 0 0 0-1 1.1h-12.1l.2-.6-.2-.5h6.1a.44 .44 0 0 0 .6 .5 .44 .44 0 0 0 .2-.7 .44 .44 0 0 0-.7 .1l-6.2 .1-.7-.4h10.3a1.18 1.18 0 0 0 1.1 1.3 1.18 1.18 0 0 0 1.2-1.3h5.7v.2a1.18 1.18 0 0 0 1.8 .9 1.18 1.18 0 0 0 0-2 1.18 1.18 0 0 0-1.8 .9h-5.7v-.2a1.18 1.18 0 0 0-1.3-.9 1.18 1.18 0 0 0-1 1.1h-10.3a.98 .98 0 0 0-1.1 .9h-10l-.1-.5-.3-.1-.5 .3-34.9-.1a1.18 1.18 0 0 0-.8-1.6 1.18 1.18 0 0 0-1.4 1.1h-5.7v-.2a1.18 1.18 0 0 0-1.3-.9 1.18 1.18 0 0 0-1 1.1h-.4v-1.5h2.9a1.18 1.18 0 0 0 1.1 1.3 1.18 1.18 0 0 0 1.2-1.3h.7v.2a1.18 1.18 0 0 0 1.2 1.1 1.18 1.18 0 0 0 1.1-1.2h18.8l.3 .5h.5a.46 .46 0 0 0-.1 .6 .46 .46 0 0 0 .7 0 .46 .46 0 0 0 0-.7l-.6 .1-.1-.7h15.8l.4 .5 .6-.4 .6 .3 .3-.4h6.7l.2 .4 .3 .1 .4-.6h3.1l.2 .8 .6-.5 .3 .3-.5 .6 .8 .2 .6-.2-.5-.6 .3-.3 .6 .5 .2-.7h4.4l.3 .5 .5-.4h6.4a1.18 1.18 0 0 0 1.1 1.3 1.18 1.18 0 0 0 1.2-1.3h.7v.2a1.18 1.18 0 0 0 1.8 .9 1.18 1.18 0 0 0 0-2 1.18 1.18 0 0 0-1.8 .9h-.7v-.2a1.18 1.18 0 0 0-1.3-.9 1.18 1.18 0 0 0-1 1.1h-6.4l-.4-.5-.4 .4h-4.4l-.2-.7-.6 .6-.3-.4 .5-.6h1.4l.4 .5 .4-.1 .1-.4 4.6 .2a.48 .48 0 0 0 .8 .3 .48 .48 0 0 0 0-.8h2v.2a1.18 1.18 0 0 0 1.2 1.1 1.18 1.18 0 0 0 1.1-1.3h5.7v.2a1.18 1.18 0 0 0 1.8 .9 1.18 1.18 0 0 0 0-2 1.18 1.18 0 0 0-1.8 .9h-5.7v-.2a1.18 1.18 0 0 0-1.3-.9 1.18 1.18 0 0 0-1 1.1l-2.3-.1-.5 .4h-4.6l-.4-.3-.5 .3-2.2-.2-.6 .2 .5 .6-.3 .4-.6-.6-.2 .6h-3.1l-.5-.3-.4 .4h-6.7l-.4-.4-.6 .3-.5-.3-.4 .4-16.1-.2-.4 .4h-18.8a1.18 1.18 0 0 0-1.1-1.2 1.18 1.18 0 0 0-1.2 1.1h-.7v-.2a1.18 1.18 0 0 0-1.3-.9 1.18 1.18 0 0 0-1 1.1h-2.9v-1.5h.4v.2a1.18 1.18 0 0 0 1.2 1.1 1.18 1.18 0 0 0 1.1-1.3h5.7v.2a1.18 1.18 0 0 0 .9 1 1.18 1.18 0 0 0 1.3-.6l24.3 .1a.44 .44 0 0 0 .6 .3 .44 .44 0 0 0 0-.7 .44 .44 0 0 0-.6 .3h-24.3l.1-.6-.3-.7h4.1l.3 .5h.5a.47 .47 0 0 0 0 .6 .47 .47 0 0 0 .6 .1 .47 .47 0 0 0 .1-.7l24.2 .2a.44 .44 0 0 0 .7 .3 .44 .44 0 0 0 0-.8 .44 .44 0 0 0-.7 .3h-24.7a.59 .59 0 0 0-.8-.8l-.2 .3h-4.1a1.18 1.18 0 0 0-1.2-.3 1.18 1.18 0 0 0-.8 1h-5.7v-.2a1.18 1.18 0 0 0-1.3-.9 1.18 1.18 0 0 0-1 1.1h-.4v-1.5h2.9a1.18 1.18 0 0 0 1.1 1.3 1.18 1.18 0 0 0 1.2-1.3h.7v.2a1.18 1.18 0 0 0 1.2 1.1 1.18 1.18 0 0 0 1.1-1.2l23.4 .1a.44 .44 0 0 0 .6 .3 .44 .44 0 0 0 0-.7 .44 .44 0 0 0-.6 .3l-23.4-.1a1.18 1.18 0 0 0-1.2-1.1 1.18 1.18 0 0 0-1.1 1.1h-.7v-.2a1.18 1.18 0 0 0-1.3-.9 1.18 1.18 0 0 0-1 1.1h-2.9v-6.6h.3l.6-.5 .4 .3-.6 .6a1.58 1.58 0 0 0 1.7 0l.2 1.1a1.25 1.25 0 0 0-1.9-.2 1.25 1.25 0 0 0 .1 1.9 1.25 1.25 0 0 0 1.8-.3l-.1 1.6a1.2 1.2 0 0 0-2 .1 1.2 1.2 0 0 0 1.1 1.8 1.2 1.2 0 0 0 1-1.8l.8-.6 .4 .3-.6 .6 .5 .2h4.7a1.18 1.18 0 0 0 .5 1.1 1.18 1.18 0 0 0 1.3-.1h47.7l.3 .5h.6a.45 .45 0 0 0 .2 .7 .45 .45 0 0 0 .6-.4h.7l.1 .4 .4 .1 .3-.3-.1-.5h9.3a1.18 1.18 0 0 0 1.1 1.3 1.18 1.18 0 0 0 1.2-1.3h.7v.2a1.18 1.18 0 0 0 1.8 .9 1.18 1.18 0 0 0 0-2 1.18 1.18 0 0 0-1.8 .9h-.7v-.2a1.18 1.18 0 0 0-1.3-.9 1.18 1.18 0 0 0-1 1.1l-9.7-.1-.3 .4h-.7l-.3-.4h-.6a.46 .46 0 0 0-.1-.7 .46 .46 0 0 0-.7 .3h-47.7l.5-.7h32.3a.43 .43 0 0 0 .6 .4 .43 .43 0 0 0 0-.7h24.2v.2a1.18 1.18 0 0 0 1.2 1.1 1.18 1.18 0 0 0 1.1-1.3h5.7v.2a1.18 1.18 0 0 0 1.8 .9 1.18 1.18 0 0 0 0-2 1.18 1.18 0 0 0-1.8 .9h-5.7v-.2a1.18 1.18 0 0 0-1.3-.9 1.18 1.18 0 0 0-1 1.1l-24.4-.1-.4 .4h-32.3a1.18 1.18 0 0 0-1-1.4 1.18 1.18 0 0 0-1.3 1.1h-3.8l.3-.2-.6-.6 .4-.3 .6 .5 .2-.9h.4a1.18 1.18 0 0 0 1.1 1.3 1.18 1.18 0 0 0 1.2-1.3h62.1v.2a1.18 1.18 0 0 0 1.2 1.1 1.18 1.18 0 0 0 1.1-1.3h.7v.2a1.18 1.18 0 0 0 1.8 .9 1.18 1.18 0 0 0 0-2 1.18 1.18 0 0 0-1.8 .9h-.7v-.2a1.18 1.18 0 0 0-1.3-.9 1.18 1.18 0 0 0-1 1.1h-62.1v-.2a1.18 1.18 0 0 0-1.3-.9 1.18 1.18 0 0 0-1 1.1h-.4l-.2-.8-.6 .6-.4-.4 .6-.6-.3-.3h3.8v.2a1.18 1.18 0 0 0 1 1 1.18 1.18 0 0 0 1.2-.7l14.4 .1a.44 .44 0 0 0 .6 .3 .44 .44 0 0 0 0-.7 .44 .44 0 0 0-.6 .3h-14.4l.1-.5h57.1a1.18 1.18 0 0 0 1.1 1.3 1.18 1.18 0 0 0 1.2-1.3h5.7v.2a1.18 1.18 0 0 0 1.8 .9 1.18 1.18 0 0 0 0-2 1.18 1.18 0 0 0-1.8 .9h-5.7v-.2a1.18 1.18 0 0 0-1.3-.9 1.18 1.18 0 0 0-1 1.1h-57.1l-.1-.5 17.2 .1a.44 .44 0 0 0 .6 .3 .44 .44 0 0 0 0-.7 .44 .44 0 0 0-.6 .3h-17.3a1.18 1.18 0 0 0-1.2-.6 1.18 1.18 0 0 0-.9 1.1h-3.8l.3-.2-.6-.6 .4-.3 .6 .5 .2-.9h.4a1.18 1.18 0 0 0 1.1 1.3 1.18 1.18 0 0 0 1.2-1.3h62.1v.2a1.18 1.18 0 0 0 1.2 1.1 1.18 1.18 0 0 0 1.1-1.3h.7v.2a1.18 1.18 0 0 0 1.8 .9 1.18 1.18 0 0 0 0-2 1.18 1.18 0 0 0-1.8 .9h-.7v-.2a1.18 1.18 0 0 0-1.3-.9 1.18 1.18 0 0 0-1 1.1h-62.1v-.2a1.18 1.18 0 0 0-1.3-.9 1.18 1.18 0 0 0-1 1.1h-.4l-.2-.8-.6 .6-.4-.4 .6-.6-.3-.3h3.8v.2a1.18 1.18 0 0 0 1 1 1.18 1.18 0 0 0 1.2-.7l36.5 .1a.44 .44 0 0 0 .6 .3 .44 .44 0 0 0 0-.8 .44 .44 0 0 0-.6 .4h-36.5l.1-.6h40.7l.4 .5 .3-.1 .1-.3h15.6a1.18 1.18 0 0 0 1.1 1.3 1.18 1.18 0 0 0 1.2-1.3h5.7v.2a1.18 1.18 0 0 0 1.8 .9 1.18 1.18 0 0 0 0-2 1.18 1.18 0 0 0-1.8 .9h-5.7v-.2a1.18 1.18 0 0 0-1.3-.9 1.18 1.18 0 0 0-1 1.1h-15.6l-.3-.4-.5 .3h-40.7a1.18 1.18 0 0 0-1.2-1 1.18 1.18 0 0 0-1.1 1.1h-3.8l.3-.2-.6-.6 .4-.3 .6 .5 .2-.9h.4a1.18 1.18 0 0 0 1 1.2 1.18 1.18 0 0 0 1.3-.9h13.1l.3 .5 14.5-.1a.44 .44 0 0 0 .6 .5 .44 .44 0 0 0 .2-.8 .44 .44 0 0 0-.7 .2l-14.2 .1 .1-.4-.3-.4h6.2l.4 .5 .5-.4h41.4a1.18 1.18 0 0 0 1.6 1.2 1.18 1.18 0 0 0 .3-2 1.18 1.18 0 0 0-1.9 .7l-41.4 .1-.5-.5-.4 .4h-6.4l-.3 .4-13.1-.1a1.18 1.18 0 0 0-1.1-1.3 1.18 1.18 0 0 0-1.2 1.1h-.4l-.2-.8-.6 .6-.4-.4 .6-.6-.3-.3h3.8v.2a1.18 1.18 0 0 0 1.3 1.1 1.18 1.18 0 0 0 1-1.4l16.6 .1a.44 .44 0 0 0 .6 .3 .44 .44 0 0 0 0-.7 .44 .44 0 0 0-.6 .3h-16.6l-.5-.8h4.3l.4 .5 .5-.2h8.3a.44 .44 0 0 0 .6 .5 .44 .44 0 0 0 .1-.7 .44 .44 0 0 0-.7 .1l-8.3 .1a.43 .43 0 0 0-.3-.6 .43 .43 0 0 0-.6 .3h-4.3a1.18 1.18 0 0 0-1.8 .9h-3.8l.3-.2-.6-.6 .4-.3 .6 .5 .2-.9h.4a1.18 1.18 0 0 0 1.1 1.3 1.18 1.18 0 0 0 1.2-1.2l9.1 .1a.44 .44 0 0 0 .7 .4 .44 .44 0 0 0 0-.8 .44 .44 0 0 0-.7 .3l-9.1-.1a1.18 1.18 0 0 0-1.2-1.1 1.18 1.18 0 0 0-1.1 1.1h-.4l-.2-.8-.6 .6-.4-.4 .6-.6-.7-.2-1 .2 .6 .6-.4 .4-.8-.7 .1-.6h5.7v.2a1.18 1.18 0 0 0 1.7 .9l44.6 .1a.44 .44 0 0 0 .6 .3 .44 .44 0 0 0 0-.7 .44 .44 0 0 0-.6 .3h-44.6l.5-.5 17.2 .1a.49 .49 0 0 0 .7 .3 .49 .49 0 0 0 .2-.7h.4l.3-.3h38.4a1.28 1.28 0 0 0 .8 1.2 1.28 1.28 0 0 0 1.4-.4l-.1 1.6a1.2 1.2 0 0 0-2 .1 1.2 1.2 0 0 0 1.1 1.8 1.2 1.2 0 0 0 1-1.8l.8-.6 .4 .3-.6 .6a1.49 1.49 0 0 0 1.7 0l-.6-.6 .4-.3 .6 .5a1.5 1.5 0 0 0 0-1.7l-.6 .6-.4-.4 .5-.6a1.5 1.5 0 0 0-1.6 0l.6 .6-.4 .4-.8-.7a1.2 1.2 0 0 0-.7-1.7 1.2 1.2 0 0 0-1.5 1.1h-38.4a.49 .49 0 0 0-.7-.5 .49 .49 0 0 0-.2 .8h-.4l-.3 .3h-17.2v-1l11.8 .1a.44 .44 0 0 0 .7 .3 .44 .44 0 0 0 0-.7 .44 .44 0 0 0-.7 .3h-11.8l-.5-.5h4.2a.44 .44 0 0 0 .6 .4 .44 .44 0 0 0 .2-.7 .44 .44 0 0 0-.7 .1l-4.3 .2a1.18 1.18 0 0 0-1.7 .9h-5.7v-.2a1.2 1.2 0 0 0-1.8-.7 1.2 1.2 0 0 0-.2 1.9 1.2 1.2 0 0 0 1.9-.2v1.6a1.25 1.25 0 0 0-1.9-.2 1.25 1.25 0 0 0 .1 1.9 1.25 1.25 0 0 0 1.8-.3l-.1 1-1.1-.2-.7 .2 .6 .6-.4 .4-.6-.6-.3 .1v-7h17.3a.44 .44 0 0 0 .6 .4 .44 .44 0 0 0 .2-.7 .44 .44 0 0 0-.7 .2l-17.4 .1v-.5h36.4l.4 .5 .4-.2h4a.44 .44 0 0 0 .6 .4 .44 .44 0 0 0 .2-.7 .44 .44 0 0 0-.8 .2l-4 .1v-.4l-.3-.3-.5 .4h-36.4v-2h24.5l.4 .5 .4-.3h20.5a.44 .44 0 0 0 .6 .5 .44 .44 0 0 0 .1-.7 .44 .44 0 0 0-.7 .1l-20.5 .1-.1-.5h11.2a.44 .44 0 0 0 .6 .5 .44 .44 0 0 0 .1-.7 .44 .44 0 0 0-.7 .1h-11.5l-.4 .4h-24.5v-.5h19.9a.44 .44 0 0 0 .6 .4 .44 .44 0 0 0 0-.7l14.9 .1a.44 .44 0 0 0 .6 .3 .44 .44 0 0 0 .2-.6h2l.3 .5 .4-.2 .1-.3 3.5 .1a.44 .44 0 0 0 .7 .3 .44 .44 0 0 0 0-.7 .44 .44 0 0 0-.7 .3h-3.5l-.5-.4-.3 .4-2.5-.2-.3 .4-15.1-.1-.4 .4h-19.9v-.5l13.5 .1a.44 .44 0 0 0 .7 .3 .44 .44 0 0 0 0-.7 .44 .44 0 0 0-.7 .3h-13.5v-1l20.1 .1a.44 .44 0 0 0 .7 .3 .44 .44 0 0 0 0-.7h15.6l.4 .5 .3-.1 .2-.4 9 .1a.44 .44 0 0 0 .7 .3 .44 .44 0 0 0 0-.7 .44 .44 0 0 0-.7 .3h-9l-.5-.4-.4 .4-15.9-.1-.4 .4h-20.1v-.8h28.5a.44 .44 0 0 0 .6 .5 .44 .44 0 0 0 .2-.7 .44 .44 0 0 0-.8 .1l-28.5 .1v-.5h35.4a.44 .44 0 0 0 .5 .5 .44 .44 0 0 0 .2-.8 .44 .44 0 0 0-.7 .2l-35.4 .1v-1.3h10.7a.44 .44 0 0 0 .6 .5 .44 .44 0 0 0 .2-.7 .44 .44 0 0 0-.7 .1l-10.8 .1v-.5h12.8l.3 .5 .5-.2h27.9l.3 .5 3-.1v.2a.9 .9 0 0 0 1 .8 .9 .9 0 0 0 .8-1h.8v.2a.9 .9 0 0 0 .9 .8 .9 .9 0 0 0 .8-1h.5l.2 .8 .6-.6 .4 .3-.7 .7 .6 .2 .8-.2-.7-.7 .4-.3 .6 .6 .2-.6-.2-.7-.6 .6-.4-.4 .7-.6-.6-.2-.8 .2 .7 .6-.4 .4-.6-.6-.2 .5h-.5a.9 .9 0 0 0-.9-.8 .9 .9 0 0 0-.8 .8h-.8v-.1a.9 .9 0 0 0-1-.7 .9 .9 0 0 0-.8 .8h-2.8l.4-.3a.49 .49 0 0 0 .7-.2 .49 .49 0 0 0-.4-.7 .49 .49 0 0 0-.6 .4h-.4l-.2 .4h-27.9l-.1-.5-.4-.2-.3 .4h-12.8v-1.5h20.1l.4 .5 .3-.1 .2-.4h13.6l.4 .5 19.3-.1 .2 .4-.2 .4 .2 .6-.2 .5 .2 .5-.2 .5 .2 .5a.69 .69 0 0 0 0 1 .69 .69 0 0 0 1-.1l.3 .2 .6-.2 .4 .2 .6-.2 .4 .2 .5-.2a.61 .61 0 0 0 .8 .3 .61 .61 0 0 0 .3-.8 .61 .61 0 0 0-.7-.4l-.3 .2-.4-.2-.6 .2-.2-.1 .2-.5-.2-.5 .2-.5-.2-.6 .2-.6-.2-.4 .8 .1 .3-.2a.6 .6 0 0 0 1.1-.1 .6 .6 0 0 0-.7-.8l-.3 .2-.6-.3-.4 .3-.6-.3-.4 .3-.6-.3-.4 .3-.6-.3-.4 .3-.1 .4-18.9-.1a.44 .44 0 0 0-.2-.7 .44 .44 0 0 0-.6 .4h-13.6l-.4-.4-.5 .4h-20.1v-.5h16.1a.44 .44 0 0 0 .5 .4 .44 .44 0 0 0 .2-.7 .44 .44 0 0 0-.7 .2l-16.1 .1v-.5h26.9a.44 .44 0 0 0 .6 .5 .44 .44 0 0 0 .2-.7 .44 .44 0 0 0-.7 .1l-27 .1v-.8h16.1a.44 .44 0 0 0 .5 .5 .44 .44 0 0 0 .2-.7 .44 .44 0 0 0-.7 .1l-16.1 .1v-.6h35.6l.4 .5 .5-.2a.48 .48 0 0 0 .7 .2 .48 .48 0 0 0 0-.7l-.6 .2-.6-.3-.4 .3h-35.6v-.7h28a.44 .44 0 0 0 .6 .5 .44 .44 0 0 0 .2-.8 .44 .44 0 0 0-.8 .2l-28 .1v-.7h20.6l.4 .5 .3-.1 .2-.4h10.1l.3 .5h12.9v.1a.9 .9 0 0 0 1 .8 .9 .9 0 0 0 .8-.9h.8v.1a.9 .9 0 0 0 .9 .8 .9 .9 0 0 0 .8-1h.5l.2 .8 .6-.6 .4 .3-.7 .7 .6 .2 .8-.2-.7-.7 .4-.3 .6 .6 .2-.6-.2-.7-.6 .6-.4-.4 .7-.6-.6-.2-.8 .2 .7 .6-.4 .4-.6-.6-.2 .5h-.5a.9 .9 0 0 0-.9-.8 .9 .9 0 0 0-.8 .9h-.8v-.2a.9 .9 0 0 0-1-.7 .9 .9 0 0 0-.8 .9l-12.6-.1a.44 .44 0 0 0 .1-.7 .44 .44 0 0 0-.7 .3h-10.1l-.4-.4-.5 .4h-20.6v-.5h15.1a.44 .44 0 0 0 .5 .4 .44 .44 0 0 0 .2-.7 .44 .44 0 0 0-.7 .2l-15.1 .1 .1-.9z"/>
<path d="M200.7 95l.7-.6 .4 .3-.6 .6 .3 .3-.3 .2 .6 .6-.4 .4-.8-.7z"/>
<path d="M200.7 89l.7-.6 .4 .3-.6 .6 .3 .3-.3 .2 .6 .6-.4 .4-.8-.7z"/>
<path d="M273.6 87.5l.7-.6 .4 .3-.6 .6 .3 .3-.3 .2 .6 .6-.4 .4-.8-.7z"/>
<path d="M275.2 87.2l.4-.3 .6 .5h.3v1.4l-.3-.1-.6 .6-.4-.4 .6-.6-.3-.2 .3-.3z"/>
</g>
</svg>
